VERSION 5.7 ;
  NOWIREEXTENSIONATPIN ON ;
  DIVIDERCHAR "/" ;
  BUSBITCHARS "[]" ;
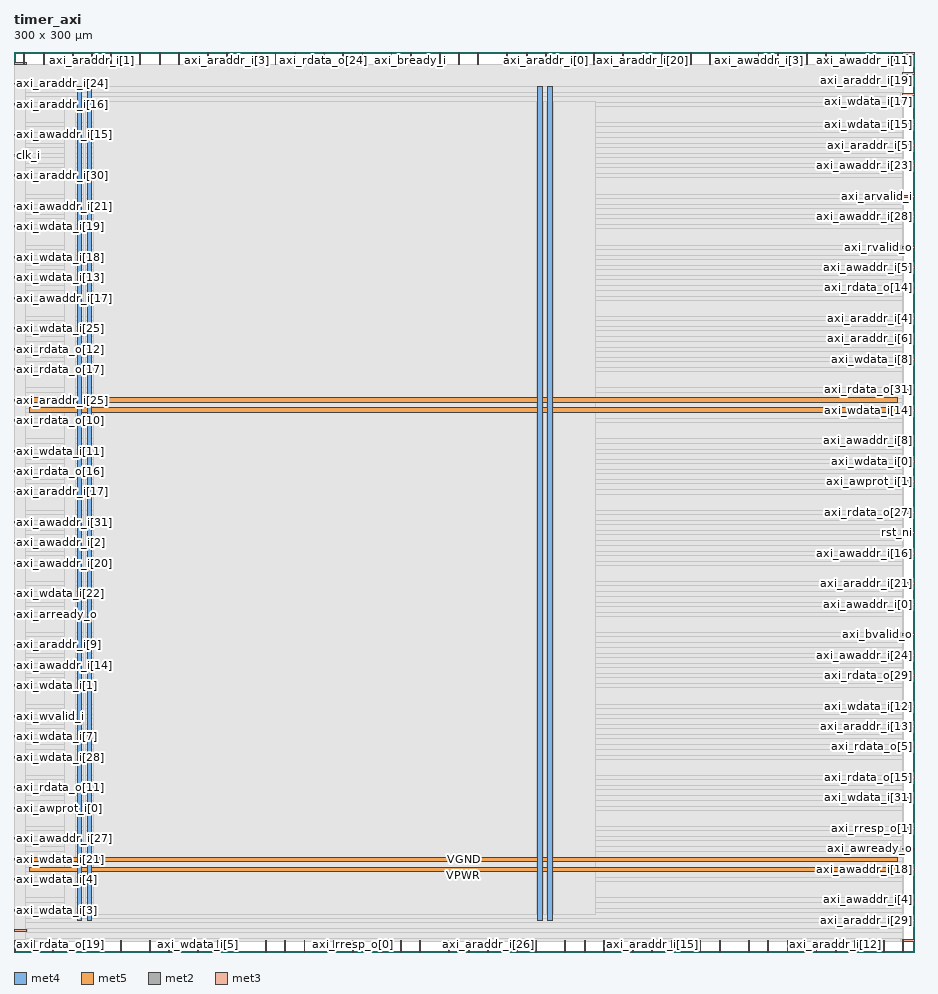
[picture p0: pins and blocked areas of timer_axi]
MACRO timer_axi
  CLASS BLOCK ;
  FOREIGN timer_axi ;
  ORIGIN 0.000 0.000 ;
  SIZE 300.000 BY 300.000 ;
  PIN VGND
    DIRECTION INOUT ;
    USE GROUND ;
    PORT
      LAYER met4 ;
        RECT 24.340 10.640 25.940 288.560 ;
    END
    PORT
      LAYER met4 ;
        RECT 177.940 10.640 179.540 288.560 ;
    END
    PORT
      LAYER met5 ;
        RECT 5.280 30.030 294.640 31.630 ;
    END
    PORT
      LAYER met5 ;
        RECT 5.280 183.210 294.640 184.810 ;
    END
  END VGND
  PIN VPWR
    DIRECTION INOUT ;
    USE POWER ;
    PORT
      LAYER met4 ;
        RECT 21.040 10.640 22.640 288.560 ;
    END
    PORT
      LAYER met4 ;
        RECT 174.640 10.640 176.240 288.560 ;
    END
    PORT
      LAYER met5 ;
        RECT 5.280 26.730 294.640 28.330 ;
    END
    PORT
      LAYER met5 ;
        RECT 5.280 179.910 294.640 181.510 ;
    END
  END VPWR
  PIN axi_araddr_i[0]
    DIRECTION INPUT ;
    USE SIGNAL ;
    PORT
      LAYER met2 ;
        RECT 177.190 296.000 177.470 300.000 ;
    END
  END axi_araddr_i[0]
  PIN axi_araddr_i[10]
    DIRECTION INPUT ;
    USE SIGNAL ;
    PORT
      LAYER met2 ;
        RECT 19.410 296.000 19.690 300.000 ;
    END
  END axi_araddr_i[10]
  PIN axi_araddr_i[11]
    DIRECTION INPUT ;
    USE SIGNAL ;
    PORT
      LAYER met2 ;
        RECT 141.770 296.000 142.050 300.000 ;
    END
  END axi_araddr_i[11]
  PIN axi_araddr_i[12]
    DIRECTION INPUT ;
    USE SIGNAL ;
    PORT
      LAYER met2 ;
        RECT 273.790 0.000 274.070 4.000 ;
    END
  END axi_araddr_i[12]
  PIN axi_araddr_i[13]
    DIRECTION INPUT ;
    USE SIGNAL ;
    PORT
      LAYER met3 ;
        RECT 296.000 74.840 300.000 75.440 ;
    END
  END axi_araddr_i[13]
  PIN axi_araddr_i[14]
    DIRECTION INPUT ;
    USE SIGNAL ;
    PORT
      LAYER met2 ;
        RECT 164.310 296.000 164.590 300.000 ;
    END
  END axi_araddr_i[14]
  PIN axi_araddr_i[15]
    DIRECTION INPUT ;
    USE SIGNAL ;
    PORT
      LAYER met2 ;
        RECT 212.610 0.000 212.890 4.000 ;
    END
  END axi_araddr_i[15]
  PIN axi_araddr_i[16]
    DIRECTION INPUT ;
    USE SIGNAL ;
    PORT
      LAYER met3 ;
        RECT 0.000 282.240 4.000 282.840 ;
    END
  END axi_araddr_i[16]
  PIN axi_araddr_i[17]
    DIRECTION INPUT ;
    USE SIGNAL ;
    PORT
      LAYER met3 ;
        RECT 0.000 153.040 4.000 153.640 ;
    END
  END axi_araddr_i[17]
  PIN axi_araddr_i[18]
    DIRECTION INPUT ;
    USE SIGNAL ;
    PORT
      LAYER met2 ;
        RECT 87.030 296.000 87.310 300.000 ;
    END
  END axi_araddr_i[18]
  PIN axi_araddr_i[19]
    DIRECTION INPUT ;
    USE SIGNAL ;
    PORT
      LAYER met3 ;
        RECT 296.000 292.440 300.000 293.040 ;
    END
  END axi_araddr_i[19]
  PIN axi_araddr_i[1]
    DIRECTION INPUT ;
    USE SIGNAL ;
    PORT
      LAYER met2 ;
        RECT 25.850 296.000 26.130 300.000 ;
    END
  END axi_araddr_i[1]
  PIN axi_araddr_i[20]
    DIRECTION INPUT ;
    USE SIGNAL ;
    PORT
      LAYER met2 ;
        RECT 209.390 296.000 209.670 300.000 ;
    END
  END axi_araddr_i[20]
  PIN axi_araddr_i[21]
    DIRECTION INPUT ;
    USE SIGNAL ;
    PORT
      LAYER met3 ;
        RECT 296.000 122.440 300.000 123.040 ;
    END
  END axi_araddr_i[21]
  PIN axi_araddr_i[22]
    DIRECTION INPUT ;
    USE SIGNAL ;
    PORT
      LAYER met2 ;
        RECT 125.670 296.000 125.950 300.000 ;
    END
  END axi_araddr_i[22]
  PIN axi_araddr_i[23]
    DIRECTION INPUT ;
    USE SIGNAL ;
    PORT
      LAYER met2 ;
        RECT 257.690 0.000 257.970 4.000 ;
    END
  END axi_araddr_i[23]
  PIN axi_araddr_i[24]
    DIRECTION INPUT ;
    USE SIGNAL ;
    PORT
      LAYER met3 ;
        RECT 0.000 289.040 4.000 289.640 ;
    END
  END axi_araddr_i[24]
  PIN axi_araddr_i[25]
    DIRECTION INPUT ;
    USE SIGNAL ;
    PORT
      LAYER met3 ;
        RECT 0.000 183.640 4.000 184.240 ;
    END
  END axi_araddr_i[25]
  PIN axi_araddr_i[26]
    DIRECTION INPUT ;
    USE SIGNAL ;
    PORT
      LAYER met2 ;
        RECT 157.870 0.000 158.150 4.000 ;
    END
  END axi_araddr_i[26]
  PIN axi_araddr_i[27]
    DIRECTION INPUT ;
    USE SIGNAL ;
    PORT
      LAYER met2 ;
        RECT 228.710 0.000 228.990 4.000 ;
    END
  END axi_araddr_i[27]
  PIN axi_araddr_i[28]
    DIRECTION INPUT ;
    USE SIGNAL ;
    PORT
      LAYER met3 ;
        RECT 0.000 295.840 4.000 296.440 ;
    END
  END axi_araddr_i[28]
  PIN axi_araddr_i[29]
    DIRECTION INPUT ;
    USE SIGNAL ;
    PORT
      LAYER met3 ;
        RECT 296.000 10.240 300.000 10.840 ;
    END
  END axi_araddr_i[29]
  PIN axi_araddr_i[2]
    DIRECTION INPUT ;
    USE SIGNAL ;
    ANTENNAGATEAREA 0.213000 ;
    PORT
      LAYER met2 ;
        RECT 45.170 0.000 45.450 4.000 ;
    END
  END axi_araddr_i[2]
  PIN axi_araddr_i[30]
    DIRECTION INPUT ;
    USE SIGNAL ;
    PORT
      LAYER met3 ;
        RECT 0.000 258.440 4.000 259.040 ;
    END
  END axi_araddr_i[30]
  PIN axi_araddr_i[31]
    DIRECTION INPUT ;
    USE SIGNAL ;
    PORT
      LAYER met2 ;
        RECT 193.290 296.000 193.570 300.000 ;
    END
  END axi_araddr_i[31]
  PIN axi_araddr_i[3]
    DIRECTION INPUT ;
    USE SIGNAL ;
    ANTENNAGATEAREA 0.159000 ;
    PORT
      LAYER met2 ;
        RECT 70.930 296.000 71.210 300.000 ;
    END
  END axi_araddr_i[3]
  PIN axi_araddr_i[4]
    DIRECTION INPUT ;
    USE SIGNAL ;
    ANTENNAGATEAREA 0.213000 ;
    PORT
      LAYER met3 ;
        RECT 296.000 210.840 300.000 211.440 ;
    END
  END axi_araddr_i[4]
  PIN axi_araddr_i[5]
    DIRECTION INPUT ;
    USE SIGNAL ;
    PORT
      LAYER met3 ;
        RECT 296.000 268.640 300.000 269.240 ;
    END
  END axi_araddr_i[5]
  PIN axi_araddr_i[6]
    DIRECTION INPUT ;
    USE SIGNAL ;
    PORT
      LAYER met3 ;
        RECT 296.000 204.040 300.000 204.640 ;
    END
  END axi_araddr_i[6]
  PIN axi_araddr_i[7]
    DIRECTION INPUT ;
    USE SIGNAL ;
    PORT
      LAYER met3 ;
        RECT 296.000 299.240 300.000 299.840 ;
    END
  END axi_araddr_i[7]
  PIN axi_araddr_i[8]
    DIRECTION INPUT ;
    USE SIGNAL ;
    PORT
      LAYER met2 ;
        RECT 122.450 0.000 122.730 4.000 ;
    END
  END axi_araddr_i[8]
  PIN axi_araddr_i[9]
    DIRECTION INPUT ;
    USE SIGNAL ;
    PORT
      LAYER met3 ;
        RECT 0.000 102.040 4.000 102.640 ;
    END
  END axi_araddr_i[9]
  PIN axi_arprot_i[0]
    DIRECTION INPUT ;
    USE SIGNAL ;
    PORT
      LAYER met2 ;
        RECT 231.930 296.000 232.210 300.000 ;
    END
  END axi_arprot_i[0]
  PIN axi_arprot_i[1]
    DIRECTION INPUT ;
    USE SIGNAL ;
    PORT
      LAYER met2 ;
        RECT 96.690 0.000 96.970 4.000 ;
    END
  END axi_arprot_i[1]
  PIN axi_arprot_i[2]
    DIRECTION INPUT ;
    USE SIGNAL ;
    PORT
      LAYER met2 ;
        RECT 219.050 0.000 219.330 4.000 ;
    END
  END axi_arprot_i[2]
  PIN axi_arready_o
    DIRECTION OUTPUT TRISTATE ;
    USE SIGNAL ;
    ANTENNADIFFAREA 0.795200 ;
    PORT
      LAYER met3 ;
        RECT 0.000 112.240 4.000 112.840 ;
    END
  END axi_arready_o
  PIN axi_arvalid_i
    DIRECTION INPUT ;
    USE SIGNAL ;
    ANTENNAGATEAREA 0.159000 ;
    PORT
      LAYER met3 ;
        RECT 296.000 251.640 300.000 252.240 ;
    END
  END axi_arvalid_i
  PIN axi_awaddr_i[0]
    DIRECTION INPUT ;
    USE SIGNAL ;
    PORT
      LAYER met3 ;
        RECT 296.000 115.640 300.000 116.240 ;
    END
  END axi_awaddr_i[0]
  PIN axi_awaddr_i[10]
    DIRECTION INPUT ;
    USE SIGNAL ;
    PORT
      LAYER met2 ;
        RECT 116.010 296.000 116.290 300.000 ;
    END
  END axi_awaddr_i[10]
  PIN axi_awaddr_i[11]
    DIRECTION INPUT ;
    USE SIGNAL ;
    PORT
      LAYER met2 ;
        RECT 286.670 296.000 286.950 300.000 ;
    END
  END axi_awaddr_i[11]
  PIN axi_awaddr_i[12]
    DIRECTION INPUT ;
    USE SIGNAL ;
    PORT
      LAYER met2 ;
        RECT 173.970 0.000 174.250 4.000 ;
    END
  END axi_awaddr_i[12]
  PIN axi_awaddr_i[13]
    DIRECTION INPUT ;
    USE SIGNAL ;
    PORT
      LAYER met2 ;
        RECT 22.630 0.000 22.910 4.000 ;
    END
  END axi_awaddr_i[13]
  PIN axi_awaddr_i[14]
    DIRECTION INPUT ;
    USE SIGNAL ;
    PORT
      LAYER met3 ;
        RECT 0.000 95.240 4.000 95.840 ;
    END
  END axi_awaddr_i[14]
  PIN axi_awaddr_i[15]
    DIRECTION INPUT ;
    USE SIGNAL ;
    PORT
      LAYER met3 ;
        RECT 0.000 272.040 4.000 272.640 ;
    END
  END axi_awaddr_i[15]
  PIN axi_awaddr_i[16]
    DIRECTION INPUT ;
    USE SIGNAL ;
    PORT
      LAYER met3 ;
        RECT 296.000 132.640 300.000 133.240 ;
    END
  END axi_awaddr_i[16]
  PIN axi_awaddr_i[17]
    DIRECTION INPUT ;
    USE SIGNAL ;
    PORT
      LAYER met3 ;
        RECT 0.000 217.640 4.000 218.240 ;
    END
  END axi_awaddr_i[17]
  PIN axi_awaddr_i[18]
    DIRECTION INPUT ;
    USE SIGNAL ;
    PORT
      LAYER met3 ;
        RECT 296.000 27.240 300.000 27.840 ;
    END
  END axi_awaddr_i[18]
  PIN axi_awaddr_i[19]
    DIRECTION INPUT ;
    USE SIGNAL ;
    PORT
      LAYER met2 ;
        RECT 186.850 296.000 187.130 300.000 ;
    END
  END axi_awaddr_i[19]
  PIN axi_awaddr_i[1]
    DIRECTION INPUT ;
    USE SIGNAL ;
    PORT
      LAYER met2 ;
        RECT 238.370 296.000 238.650 300.000 ;
    END
  END axi_awaddr_i[1]
  PIN axi_awaddr_i[20]
    DIRECTION INPUT ;
    USE SIGNAL ;
    PORT
      LAYER met3 ;
        RECT 0.000 129.240 4.000 129.840 ;
    END
  END axi_awaddr_i[20]
  PIN axi_awaddr_i[21]
    DIRECTION INPUT ;
    USE SIGNAL ;
    PORT
      LAYER met3 ;
        RECT 0.000 248.240 4.000 248.840 ;
    END
  END axi_awaddr_i[21]
  PIN axi_awaddr_i[22]
    DIRECTION INPUT ;
    USE SIGNAL ;
    PORT
      LAYER met2 ;
        RECT 202.950 296.000 203.230 300.000 ;
    END
  END axi_awaddr_i[22]
  PIN axi_awaddr_i[23]
    DIRECTION INPUT ;
    USE SIGNAL ;
    PORT
      LAYER met3 ;
        RECT 296.000 261.840 300.000 262.440 ;
    END
  END axi_awaddr_i[23]
  PIN axi_awaddr_i[24]
    DIRECTION INPUT ;
    USE SIGNAL ;
    PORT
      LAYER met3 ;
        RECT 296.000 98.640 300.000 99.240 ;
    END
  END axi_awaddr_i[24]
  PIN axi_awaddr_i[25]
    DIRECTION INPUT ;
    USE SIGNAL ;
    PORT
      LAYER met2 ;
        RECT 277.010 296.000 277.290 300.000 ;
    END
  END axi_awaddr_i[25]
  PIN axi_awaddr_i[26]
    DIRECTION INPUT ;
    USE SIGNAL ;
    PORT
      LAYER met2 ;
        RECT 74.150 0.000 74.430 4.000 ;
    END
  END axi_awaddr_i[26]
  PIN axi_awaddr_i[27]
    DIRECTION INPUT ;
    USE SIGNAL ;
    PORT
      LAYER met3 ;
        RECT 0.000 37.440 4.000 38.040 ;
    END
  END axi_awaddr_i[27]
  PIN axi_awaddr_i[28]
    DIRECTION INPUT ;
    USE SIGNAL ;
    PORT
      LAYER met3 ;
        RECT 296.000 244.840 300.000 245.440 ;
    END
  END axi_awaddr_i[28]
  PIN axi_awaddr_i[29]
    DIRECTION INPUT ;
    USE SIGNAL ;
    PORT
      LAYER met2 ;
        RECT 90.250 0.000 90.530 4.000 ;
    END
  END axi_awaddr_i[29]
  PIN axi_awaddr_i[2]
    DIRECTION INPUT ;
    USE SIGNAL ;
    ANTENNAGATEAREA 0.213000 ;
    PORT
      LAYER met3 ;
        RECT 0.000 136.040 4.000 136.640 ;
    END
  END axi_awaddr_i[2]
  PIN axi_awaddr_i[30]
    DIRECTION INPUT ;
    USE SIGNAL ;
    PORT
      LAYER met2 ;
        RECT 190.070 0.000 190.350 4.000 ;
    END
  END axi_awaddr_i[30]
  PIN axi_awaddr_i[31]
    DIRECTION INPUT ;
    USE SIGNAL ;
    PORT
      LAYER met3 ;
        RECT 0.000 142.840 4.000 143.440 ;
    END
  END axi_awaddr_i[31]
  PIN axi_awaddr_i[3]
    DIRECTION INPUT ;
    USE SIGNAL ;
    ANTENNAGATEAREA 0.247500 ;
    PORT
      LAYER met2 ;
        RECT 248.030 296.000 248.310 300.000 ;
    END
  END axi_awaddr_i[3]
  PIN axi_awaddr_i[4]
    DIRECTION INPUT ;
    USE SIGNAL ;
    ANTENNAGATEAREA 0.213000 ;
    PORT
      LAYER met3 ;
        RECT 296.000 17.040 300.000 17.640 ;
    END
  END axi_awaddr_i[4]
  PIN axi_awaddr_i[5]
    DIRECTION INPUT ;
    USE SIGNAL ;
    PORT
      LAYER met3 ;
        RECT 296.000 227.840 300.000 228.440 ;
    END
  END axi_awaddr_i[5]
  PIN axi_awaddr_i[6]
    DIRECTION INPUT ;
    USE SIGNAL ;
    PORT
      LAYER met2 ;
        RECT 128.890 0.000 129.170 4.000 ;
    END
  END axi_awaddr_i[6]
  PIN axi_awaddr_i[7]
    DIRECTION INPUT ;
    USE SIGNAL ;
    PORT
      LAYER met2 ;
        RECT 196.510 0.000 196.790 4.000 ;
    END
  END axi_awaddr_i[7]
  PIN axi_awaddr_i[8]
    DIRECTION INPUT ;
    USE SIGNAL ;
    PORT
      LAYER met3 ;
        RECT 296.000 170.040 300.000 170.640 ;
    END
  END axi_awaddr_i[8]
  PIN axi_awaddr_i[9]
    DIRECTION INPUT ;
    USE SIGNAL ;
    PORT
      LAYER met2 ;
        RECT 83.810 0.000 84.090 4.000 ;
    END
  END axi_awaddr_i[9]
  PIN axi_awprot_i[0]
    DIRECTION INPUT ;
    USE SIGNAL ;
    PORT
      LAYER met3 ;
        RECT 0.000 47.640 4.000 48.240 ;
    END
  END axi_awprot_i[0]
  PIN axi_awprot_i[1]
    DIRECTION INPUT ;
    USE SIGNAL ;
    PORT
      LAYER met3 ;
        RECT 296.000 156.440 300.000 157.040 ;
    END
  END axi_awprot_i[1]
  PIN axi_awprot_i[2]
    DIRECTION INPUT ;
    USE SIGNAL ;
    PORT
      LAYER met2 ;
        RECT 267.350 0.000 267.630 4.000 ;
    END
  END axi_awprot_i[2]
  PIN axi_awready_o
    DIRECTION OUTPUT TRISTATE ;
    USE SIGNAL ;
    ANTENNADIFFAREA 0.795200 ;
    PORT
      LAYER met3 ;
        RECT 296.000 34.040 300.000 34.640 ;
    END
  END axi_awready_o
  PIN axi_awvalid_i
    DIRECTION INPUT ;
    USE SIGNAL ;
    ANTENNAGATEAREA 0.213000 ;
    PORT
      LAYER met2 ;
        RECT 93.470 296.000 93.750 300.000 ;
    END
  END axi_awvalid_i
  PIN axi_bready_i
    DIRECTION INPUT ;
    USE SIGNAL ;
    ANTENNAGATEAREA 0.196500 ;
    PORT
      LAYER met2 ;
        RECT 132.110 296.000 132.390 300.000 ;
    END
  END axi_bready_i
  PIN axi_bresp_o[0]
    DIRECTION OUTPUT TRISTATE ;
    USE SIGNAL ;
    PORT
      LAYER met2 ;
        RECT 9.750 296.000 10.030 300.000 ;
    END
  END axi_bresp_o[0]
  PIN axi_bresp_o[1]
    DIRECTION OUTPUT TRISTATE ;
    USE SIGNAL ;
    PORT
      LAYER met2 ;
        RECT 293.110 296.000 293.390 300.000 ;
    END
  END axi_bresp_o[1]
  PIN axi_bvalid_o
    DIRECTION OUTPUT TRISTATE ;
    USE SIGNAL ;
    ANTENNADIFFAREA 0.445500 ;
    PORT
      LAYER met3 ;
        RECT 296.000 105.440 300.000 106.040 ;
    END
  END axi_bvalid_o
  PIN axi_rdata_o[0]
    DIRECTION OUTPUT TRISTATE ;
    USE SIGNAL ;
    ANTENNADIFFAREA 0.795200 ;
    PORT
      LAYER met2 ;
        RECT 135.330 0.000 135.610 4.000 ;
    END
  END axi_rdata_o[0]
  PIN axi_rdata_o[10]
    DIRECTION OUTPUT TRISTATE ;
    USE SIGNAL ;
    ANTENNADIFFAREA 0.795200 ;
    PORT
      LAYER met3 ;
        RECT 0.000 176.840 4.000 177.440 ;
    END
  END axi_rdata_o[10]
  PIN axi_rdata_o[11]
    DIRECTION OUTPUT TRISTATE ;
    USE SIGNAL ;
    ANTENNADIFFAREA 0.795200 ;
    PORT
      LAYER met3 ;
        RECT 0.000 54.440 4.000 55.040 ;
    END
  END axi_rdata_o[11]
  PIN axi_rdata_o[12]
    DIRECTION OUTPUT TRISTATE ;
    USE SIGNAL ;
    ANTENNADIFFAREA 0.795200 ;
    PORT
      LAYER met3 ;
        RECT 0.000 200.640 4.000 201.240 ;
    END
  END axi_rdata_o[12]
  PIN axi_rdata_o[13]
    DIRECTION OUTPUT TRISTATE ;
    USE SIGNAL ;
    ANTENNADIFFAREA 0.795200 ;
    PORT
      LAYER met2 ;
        RECT 235.150 0.000 235.430 4.000 ;
    END
  END axi_rdata_o[13]
  PIN axi_rdata_o[14]
    DIRECTION OUTPUT TRISTATE ;
    USE SIGNAL ;
    ANTENNADIFFAREA 0.445500 ;
    PORT
      LAYER met3 ;
        RECT 296.000 221.040 300.000 221.640 ;
    END
  END axi_rdata_o[14]
  PIN axi_rdata_o[15]
    DIRECTION OUTPUT TRISTATE ;
    USE SIGNAL ;
    ANTENNADIFFAREA 0.445500 ;
    PORT
      LAYER met3 ;
        RECT 296.000 57.840 300.000 58.440 ;
    END
  END axi_rdata_o[15]
  PIN axi_rdata_o[16]
    DIRECTION OUTPUT TRISTATE ;
    USE SIGNAL ;
    ANTENNADIFFAREA 0.795200 ;
    PORT
      LAYER met3 ;
        RECT 0.000 159.840 4.000 160.440 ;
    END
  END axi_rdata_o[16]
  PIN axi_rdata_o[17]
    DIRECTION OUTPUT TRISTATE ;
    USE SIGNAL ;
    ANTENNADIFFAREA 0.795200 ;
    PORT
      LAYER met3 ;
        RECT 0.000 193.840 4.000 194.440 ;
    END
  END axi_rdata_o[17]
  PIN axi_rdata_o[18]
    DIRECTION OUTPUT TRISTATE ;
    USE SIGNAL ;
    ANTENNADIFFAREA 0.795200 ;
    PORT
      LAYER met2 ;
        RECT 254.470 296.000 254.750 300.000 ;
    END
  END axi_rdata_o[18]
  PIN axi_rdata_o[19]
    DIRECTION OUTPUT TRISTATE ;
    USE SIGNAL ;
    ANTENNADIFFAREA 0.795200 ;
    PORT
      LAYER met2 ;
        RECT 6.530 0.000 6.810 4.000 ;
    END
  END axi_rdata_o[19]
  PIN axi_rdata_o[1]
    DIRECTION OUTPUT TRISTATE ;
    USE SIGNAL ;
    ANTENNADIFFAREA 0.795200 ;
    PORT
      LAYER met2 ;
        RECT 48.390 296.000 48.670 300.000 ;
    END
  END axi_rdata_o[1]
  PIN axi_rdata_o[20]
    DIRECTION OUTPUT TRISTATE ;
    USE SIGNAL ;
    ANTENNADIFFAREA 0.795200 ;
    PORT
      LAYER met3 ;
        RECT 296.000 3.440 300.000 4.040 ;
    END
  END axi_rdata_o[20]
  PIN axi_rdata_o[21]
    DIRECTION OUTPUT TRISTATE ;
    USE SIGNAL ;
    ANTENNADIFFAREA 0.795200 ;
    PORT
      LAYER met2 ;
        RECT 41.950 296.000 42.230 300.000 ;
    END
  END axi_rdata_o[21]
  PIN axi_rdata_o[22]
    DIRECTION OUTPUT TRISTATE ;
    USE SIGNAL ;
    ANTENNADIFFAREA 0.795200 ;
    PORT
      LAYER met2 ;
        RECT 109.570 296.000 109.850 300.000 ;
    END
  END axi_rdata_o[22]
  PIN axi_rdata_o[23]
    DIRECTION OUTPUT TRISTATE ;
    USE SIGNAL ;
    ANTENNADIFFAREA 0.795200 ;
    PORT
      LAYER met3 ;
        RECT 0.000 6.840 4.000 7.440 ;
    END
  END axi_rdata_o[23]
  PIN axi_rdata_o[24]
    DIRECTION OUTPUT TRISTATE ;
    USE SIGNAL ;
    ANTENNADIFFAREA 0.795200 ;
    PORT
      LAYER met2 ;
        RECT 103.130 296.000 103.410 300.000 ;
    END
  END axi_rdata_o[24]
  PIN axi_rdata_o[25]
    DIRECTION OUTPUT TRISTATE ;
    USE SIGNAL ;
    ANTENNADIFFAREA 0.795200 ;
    PORT
      LAYER met2 ;
        RECT 29.070 0.000 29.350 4.000 ;
    END
  END axi_rdata_o[25]
  PIN axi_rdata_o[26]
    DIRECTION OUTPUT TRISTATE ;
    USE SIGNAL ;
    ANTENNADIFFAREA 0.795200 ;
    PORT
      LAYER met2 ;
        RECT 32.290 296.000 32.570 300.000 ;
    END
  END axi_rdata_o[26]
  PIN axi_rdata_o[27]
    DIRECTION OUTPUT TRISTATE ;
    USE SIGNAL ;
    ANTENNADIFFAREA 0.445500 ;
    PORT
      LAYER met3 ;
        RECT 296.000 146.240 300.000 146.840 ;
    END
  END axi_rdata_o[27]
  PIN axi_rdata_o[28]
    DIRECTION OUTPUT TRISTATE ;
    USE SIGNAL ;
    ANTENNADIFFAREA 0.795200 ;
    PORT
      LAYER met2 ;
        RECT 148.210 296.000 148.490 300.000 ;
    END
  END axi_rdata_o[28]
  PIN axi_rdata_o[29]
    DIRECTION OUTPUT TRISTATE ;
    USE SIGNAL ;
    ANTENNADIFFAREA 0.445500 ;
    PORT
      LAYER met3 ;
        RECT 296.000 91.840 300.000 92.440 ;
    END
  END axi_rdata_o[29]
  PIN axi_rdata_o[2]
    DIRECTION OUTPUT TRISTATE ;
    USE SIGNAL ;
    ANTENNADIFFAREA 0.795200 ;
    PORT
      LAYER met2 ;
        RECT 289.890 0.000 290.170 4.000 ;
    END
  END axi_rdata_o[2]
  PIN axi_rdata_o[30]
    DIRECTION OUTPUT TRISTATE ;
    USE SIGNAL ;
    ANTENNADIFFAREA 0.795200 ;
    PORT
      LAYER met2 ;
        RECT 151.430 0.000 151.710 4.000 ;
    END
  END axi_rdata_o[30]
  PIN axi_rdata_o[31]
    DIRECTION OUTPUT TRISTATE ;
    USE SIGNAL ;
    ANTENNADIFFAREA 0.445500 ;
    PORT
      LAYER met3 ;
        RECT 296.000 187.040 300.000 187.640 ;
    END
  END axi_rdata_o[31]
  PIN axi_rdata_o[3]
    DIRECTION OUTPUT TRISTATE ;
    USE SIGNAL ;
    ANTENNADIFFAREA 0.795200 ;
    PORT
      LAYER met2 ;
        RECT 270.570 296.000 270.850 300.000 ;
    END
  END axi_rdata_o[3]
  PIN axi_rdata_o[4]
    DIRECTION OUTPUT TRISTATE ;
    USE SIGNAL ;
    ANTENNADIFFAREA 0.795200 ;
    PORT
      LAYER met2 ;
        RECT 67.710 0.000 67.990 4.000 ;
    END
  END axi_rdata_o[4]
  PIN axi_rdata_o[5]
    DIRECTION OUTPUT TRISTATE ;
    USE SIGNAL ;
    ANTENNADIFFAREA 0.795200 ;
    PORT
      LAYER met3 ;
        RECT 296.000 68.040 300.000 68.640 ;
    END
  END axi_rdata_o[5]
  PIN axi_rdata_o[6]
    DIRECTION OUTPUT TRISTATE ;
    USE SIGNAL ;
    ANTENNADIFFAREA 0.795200 ;
    PORT
      LAYER met2 ;
        RECT 183.630 0.000 183.910 4.000 ;
    END
  END axi_rdata_o[6]
  PIN axi_rdata_o[7]
    DIRECTION OUTPUT TRISTATE ;
    USE SIGNAL ;
    ANTENNADIFFAREA 0.795200 ;
    PORT
      LAYER met2 ;
        RECT 296.330 0.000 296.610 4.000 ;
    END
  END axi_rdata_o[7]
  PIN axi_rdata_o[8]
    DIRECTION OUTPUT TRISTATE ;
    USE SIGNAL ;
    ANTENNADIFFAREA 0.795200 ;
    PORT
      LAYER met2 ;
        RECT 80.590 296.000 80.870 300.000 ;
    END
  END axi_rdata_o[8]
  PIN axi_rdata_o[9]
    DIRECTION OUTPUT TRISTATE ;
    USE SIGNAL ;
    ANTENNADIFFAREA 0.795200 ;
    PORT
      LAYER met2 ;
        RECT 244.810 0.000 245.090 4.000 ;
    END
  END axi_rdata_o[9]
  PIN axi_rready_i
    DIRECTION INPUT ;
    USE SIGNAL ;
    ANTENNAGATEAREA 0.196500 ;
    PORT
      LAYER met2 ;
        RECT 35.510 0.000 35.790 4.000 ;
    END
  END axi_rready_i
  PIN axi_rresp_o[0]
    DIRECTION OUTPUT TRISTATE ;
    USE SIGNAL ;
    PORT
      LAYER met2 ;
        RECT 112.790 0.000 113.070 4.000 ;
    END
  END axi_rresp_o[0]
  PIN axi_rresp_o[1]
    DIRECTION OUTPUT TRISTATE ;
    USE SIGNAL ;
    PORT
      LAYER met3 ;
        RECT 296.000 40.840 300.000 41.440 ;
    END
  END axi_rresp_o[1]
  PIN axi_rvalid_o
    DIRECTION OUTPUT TRISTATE ;
    USE SIGNAL ;
    ANTENNADIFFAREA 0.445500 ;
    PORT
      LAYER met3 ;
        RECT 296.000 234.640 300.000 235.240 ;
    END
  END axi_rvalid_o
  PIN axi_wdata_i[0]
    DIRECTION INPUT ;
    USE SIGNAL ;
    ANTENNAGATEAREA 0.213000 ;
    PORT
      LAYER met3 ;
        RECT 296.000 163.240 300.000 163.840 ;
    END
  END axi_wdata_i[0]
  PIN axi_wdata_i[10]
    DIRECTION INPUT ;
    USE SIGNAL ;
    ANTENNAGATEAREA 0.213000 ;
    PORT
      LAYER met2 ;
        RECT 251.250 0.000 251.530 4.000 ;
    END
  END axi_wdata_i[10]
  PIN axi_wdata_i[11]
    DIRECTION INPUT ;
    USE SIGNAL ;
    ANTENNAGATEAREA 0.196500 ;
    PORT
      LAYER met3 ;
        RECT 0.000 166.640 4.000 167.240 ;
    END
  END axi_wdata_i[11]
  PIN axi_wdata_i[12]
    DIRECTION INPUT ;
    USE SIGNAL ;
    ANTENNAGATEAREA 0.213000 ;
    PORT
      LAYER met3 ;
        RECT 296.000 81.640 300.000 82.240 ;
    END
  END axi_wdata_i[12]
  PIN axi_wdata_i[13]
    DIRECTION INPUT ;
    USE SIGNAL ;
    ANTENNAGATEAREA 0.126000 ;
    PORT
      LAYER met3 ;
        RECT 0.000 224.440 4.000 225.040 ;
    END
  END axi_wdata_i[13]
  PIN axi_wdata_i[14]
    DIRECTION INPUT ;
    USE SIGNAL ;
    ANTENNAGATEAREA 0.213000 ;
    PORT
      LAYER met3 ;
        RECT 296.000 180.240 300.000 180.840 ;
    END
  END axi_wdata_i[14]
  PIN axi_wdata_i[15]
    DIRECTION INPUT ;
    USE SIGNAL ;
    ANTENNAGATEAREA 0.159000 ;
    PORT
      LAYER met3 ;
        RECT 296.000 275.440 300.000 276.040 ;
    END
  END axi_wdata_i[15]
  PIN axi_wdata_i[16]
    DIRECTION INPUT ;
    USE SIGNAL ;
    ANTENNAGATEAREA 0.159000 ;
    PORT
      LAYER met2 ;
        RECT 280.230 0.000 280.510 4.000 ;
    END
  END axi_wdata_i[16]
  PIN axi_wdata_i[17]
    DIRECTION INPUT ;
    USE SIGNAL ;
    ANTENNAGATEAREA 0.159000 ;
    PORT
      LAYER met3 ;
        RECT 296.000 285.640 300.000 286.240 ;
    END
  END axi_wdata_i[17]
  PIN axi_wdata_i[18]
    DIRECTION INPUT ;
    USE SIGNAL ;
    ANTENNAGATEAREA 0.196500 ;
    PORT
      LAYER met3 ;
        RECT 0.000 231.240 4.000 231.840 ;
    END
  END axi_wdata_i[18]
  PIN axi_wdata_i[19]
    DIRECTION INPUT ;
    USE SIGNAL ;
    ANTENNAGATEAREA 0.196500 ;
    PORT
      LAYER met3 ;
        RECT 0.000 241.440 4.000 242.040 ;
    END
  END axi_wdata_i[19]
  PIN axi_wdata_i[1]
    DIRECTION INPUT ;
    USE SIGNAL ;
    ANTENNAGATEAREA 0.196500 ;
    PORT
      LAYER met3 ;
        RECT 0.000 88.440 4.000 89.040 ;
    END
  END axi_wdata_i[1]
  PIN axi_wdata_i[20]
    DIRECTION INPUT ;
    USE SIGNAL ;
    ANTENNAGATEAREA 0.126000 ;
    PORT
      LAYER met2 ;
        RECT 0.090 0.000 0.370 4.000 ;
    END
  END axi_wdata_i[20]
  PIN axi_wdata_i[21]
    DIRECTION INPUT ;
    USE SIGNAL ;
    ANTENNAGATEAREA 0.126000 ;
    PORT
      LAYER met3 ;
        RECT 0.000 30.640 4.000 31.240 ;
    END
  END axi_wdata_i[21]
  PIN axi_wdata_i[22]
    DIRECTION INPUT ;
    USE SIGNAL ;
    ANTENNAGATEAREA 0.196500 ;
    PORT
      LAYER met3 ;
        RECT 0.000 119.040 4.000 119.640 ;
    END
  END axi_wdata_i[22]
  PIN axi_wdata_i[23]
    DIRECTION INPUT ;
    USE SIGNAL ;
    ANTENNAGATEAREA 0.196500 ;
    PORT
      LAYER met2 ;
        RECT 64.490 296.000 64.770 300.000 ;
    END
  END axi_wdata_i[23]
  PIN axi_wdata_i[24]
    DIRECTION INPUT ;
    USE SIGNAL ;
    ANTENNAGATEAREA 0.213000 ;
    PORT
      LAYER met2 ;
        RECT 170.750 296.000 171.030 300.000 ;
    END
  END axi_wdata_i[24]
  PIN axi_wdata_i[25]
    DIRECTION INPUT ;
    USE SIGNAL ;
    ANTENNAGATEAREA 0.196500 ;
    PORT
      LAYER met3 ;
        RECT 0.000 207.440 4.000 208.040 ;
    END
  END axi_wdata_i[25]
  PIN axi_wdata_i[26]
    DIRECTION INPUT ;
    USE SIGNAL ;
    ANTENNAGATEAREA 0.126000 ;
    PORT
      LAYER met2 ;
        RECT 51.610 0.000 51.890 4.000 ;
    END
  END axi_wdata_i[26]
  PIN axi_wdata_i[27]
    DIRECTION INPUT ;
    USE SIGNAL ;
    ANTENNAGATEAREA 0.126000 ;
    PORT
      LAYER met2 ;
        RECT 12.970 0.000 13.250 4.000 ;
    END
  END axi_wdata_i[27]
  PIN axi_wdata_i[28]
    DIRECTION INPUT ;
    USE SIGNAL ;
    ANTENNAGATEAREA 0.196500 ;
    PORT
      LAYER met3 ;
        RECT 0.000 64.640 4.000 65.240 ;
    END
  END axi_wdata_i[28]
  PIN axi_wdata_i[29]
    DIRECTION INPUT ;
    USE SIGNAL ;
    ANTENNAGATEAREA 0.213000 ;
    PORT
      LAYER met2 ;
        RECT 154.650 296.000 154.930 300.000 ;
    END
  END axi_wdata_i[29]
  PIN axi_wdata_i[2]
    DIRECTION INPUT ;
    USE SIGNAL ;
    ANTENNAGATEAREA 0.196500 ;
    PORT
      LAYER met2 ;
        RECT 144.990 0.000 145.270 4.000 ;
    END
  END axi_wdata_i[2]
  PIN axi_wdata_i[30]
    DIRECTION INPUT ;
    USE SIGNAL ;
    ANTENNAGATEAREA 0.159000 ;
    PORT
      LAYER met2 ;
        RECT 264.130 296.000 264.410 300.000 ;
    END
  END axi_wdata_i[30]
  PIN axi_wdata_i[31]
    DIRECTION INPUT ;
    USE SIGNAL ;
    ANTENNAGATEAREA 0.213000 ;
    PORT
      LAYER met3 ;
        RECT 296.000 51.040 300.000 51.640 ;
    END
  END axi_wdata_i[31]
  PIN axi_wdata_i[3]
    DIRECTION INPUT ;
    USE SIGNAL ;
    ANTENNAGATEAREA 0.213000 ;
    PORT
      LAYER met3 ;
        RECT 0.000 13.640 4.000 14.240 ;
    END
  END axi_wdata_i[3]
  PIN axi_wdata_i[4]
    DIRECTION INPUT ;
    USE SIGNAL ;
    ANTENNAGATEAREA 0.196500 ;
    PORT
      LAYER met3 ;
        RECT 0.000 23.840 4.000 24.440 ;
    END
  END axi_wdata_i[4]
  PIN axi_wdata_i[5]
    DIRECTION INPUT ;
    USE SIGNAL ;
    ANTENNAGATEAREA 0.196500 ;
    PORT
      LAYER met2 ;
        RECT 61.270 0.000 61.550 4.000 ;
    END
  END axi_wdata_i[5]
  PIN axi_wdata_i[6]
    DIRECTION INPUT ;
    USE SIGNAL ;
    ANTENNAGATEAREA 0.196500 ;
    PORT
      LAYER met2 ;
        RECT 106.350 0.000 106.630 4.000 ;
    END
  END axi_wdata_i[6]
  PIN axi_wdata_i[7]
    DIRECTION INPUT ;
    USE SIGNAL ;
    ANTENNAGATEAREA 0.196500 ;
    PORT
      LAYER met3 ;
        RECT 0.000 71.440 4.000 72.040 ;
    END
  END axi_wdata_i[7]
  PIN axi_wdata_i[8]
    DIRECTION INPUT ;
    USE SIGNAL ;
    ANTENNAGATEAREA 0.159000 ;
    PORT
      LAYER met3 ;
        RECT 296.000 197.240 300.000 197.840 ;
    END
  END axi_wdata_i[8]
  PIN axi_wdata_i[9]
    DIRECTION INPUT ;
    USE SIGNAL ;
    ANTENNAGATEAREA 0.196500 ;
    PORT
      LAYER met2 ;
        RECT 167.530 0.000 167.810 4.000 ;
    END
  END axi_wdata_i[9]
  PIN axi_wready_o
    DIRECTION OUTPUT TRISTATE ;
    USE SIGNAL ;
    ANTENNADIFFAREA 0.795200 ;
    PORT
      LAYER met2 ;
        RECT 225.490 296.000 225.770 300.000 ;
    END
  END axi_wready_o
  PIN axi_wstrb_i[0]
    DIRECTION INPUT ;
    USE SIGNAL ;
    PORT
      LAYER met2 ;
        RECT 215.830 296.000 216.110 300.000 ;
    END
  END axi_wstrb_i[0]
  PIN axi_wstrb_i[1]
    DIRECTION INPUT ;
    USE SIGNAL ;
    PORT
      LAYER met2 ;
        RECT 3.310 296.000 3.590 300.000 ;
    END
  END axi_wstrb_i[1]
  PIN axi_wstrb_i[2]
    DIRECTION INPUT ;
    USE SIGNAL ;
    PORT
      LAYER met2 ;
        RECT 54.830 296.000 55.110 300.000 ;
    END
  END axi_wstrb_i[2]
  PIN axi_wstrb_i[3]
    DIRECTION INPUT ;
    USE SIGNAL ;
    PORT
      LAYER met2 ;
        RECT 206.170 0.000 206.450 4.000 ;
    END
  END axi_wstrb_i[3]
  PIN axi_wvalid_i
    DIRECTION INPUT ;
    USE SIGNAL ;
    ANTENNAGATEAREA 0.196500 ;
    PORT
      LAYER met3 ;
        RECT 0.000 78.240 4.000 78.840 ;
    END
  END axi_wvalid_i
  PIN clk_i
    DIRECTION INPUT ;
    USE SIGNAL ;
    ANTENNAGATEAREA 0.852000 ;
    PORT
      LAYER met3 ;
        RECT 0.000 265.240 4.000 265.840 ;
    END
  END clk_i
  PIN rst_ni
    DIRECTION INPUT ;
    USE SIGNAL ;
    ANTENNAGATEAREA 0.196500 ;
    PORT
      LAYER met3 ;
        RECT 296.000 139.440 300.000 140.040 ;
    END
  END rst_ni
  OBS
      LAYER li1 ;
        RECT 5.520 10.795 294.400 288.405 ;
      LAYER met1 ;
        RECT 0.070 9.900 296.630 288.560 ;
      LAYER met2 ;
        RECT 0.100 295.720 3.030 296.000 ;
        RECT 3.870 295.720 9.470 296.000 ;
        RECT 10.310 295.720 19.130 296.000 ;
        RECT 19.970 295.720 25.570 296.000 ;
        RECT 26.410 295.720 32.010 296.000 ;
        RECT 32.850 295.720 41.670 296.000 ;
        RECT 42.510 295.720 48.110 296.000 ;
        RECT 48.950 295.720 54.550 296.000 ;
        RECT 55.390 295.720 64.210 296.000 ;
        RECT 65.050 295.720 70.650 296.000 ;
        RECT 71.490 295.720 80.310 296.000 ;
        RECT 81.150 295.720 86.750 296.000 ;
        RECT 87.590 295.720 93.190 296.000 ;
        RECT 94.030 295.720 102.850 296.000 ;
        RECT 103.690 295.720 109.290 296.000 ;
        RECT 110.130 295.720 115.730 296.000 ;
        RECT 116.570 295.720 125.390 296.000 ;
        RECT 126.230 295.720 131.830 296.000 ;
        RECT 132.670 295.720 141.490 296.000 ;
        RECT 142.330 295.720 147.930 296.000 ;
        RECT 148.770 295.720 154.370 296.000 ;
        RECT 155.210 295.720 164.030 296.000 ;
        RECT 164.870 295.720 170.470 296.000 ;
        RECT 171.310 295.720 176.910 296.000 ;
        RECT 177.750 295.720 186.570 296.000 ;
        RECT 187.410 295.720 193.010 296.000 ;
        RECT 193.850 295.720 202.670 296.000 ;
        RECT 203.510 295.720 209.110 296.000 ;
        RECT 209.950 295.720 215.550 296.000 ;
        RECT 216.390 295.720 225.210 296.000 ;
        RECT 226.050 295.720 231.650 296.000 ;
        RECT 232.490 295.720 238.090 296.000 ;
        RECT 238.930 295.720 247.750 296.000 ;
        RECT 248.590 295.720 254.190 296.000 ;
        RECT 255.030 295.720 263.850 296.000 ;
        RECT 264.690 295.720 270.290 296.000 ;
        RECT 271.130 295.720 276.730 296.000 ;
        RECT 277.570 295.720 286.390 296.000 ;
        RECT 287.230 295.720 292.830 296.000 ;
        RECT 293.670 295.720 296.600 296.000 ;
        RECT 0.100 4.280 296.600 295.720 ;
        RECT 0.650 3.555 6.250 4.280 ;
        RECT 7.090 3.555 12.690 4.280 ;
        RECT 13.530 3.555 22.350 4.280 ;
        RECT 23.190 3.555 28.790 4.280 ;
        RECT 29.630 3.555 35.230 4.280 ;
        RECT 36.070 3.555 44.890 4.280 ;
        RECT 45.730 3.555 51.330 4.280 ;
        RECT 52.170 3.555 60.990 4.280 ;
        RECT 61.830 3.555 67.430 4.280 ;
        RECT 68.270 3.555 73.870 4.280 ;
        RECT 74.710 3.555 83.530 4.280 ;
        RECT 84.370 3.555 89.970 4.280 ;
        RECT 90.810 3.555 96.410 4.280 ;
        RECT 97.250 3.555 106.070 4.280 ;
        RECT 106.910 3.555 112.510 4.280 ;
        RECT 113.350 3.555 122.170 4.280 ;
        RECT 123.010 3.555 128.610 4.280 ;
        RECT 129.450 3.555 135.050 4.280 ;
        RECT 135.890 3.555 144.710 4.280 ;
        RECT 145.550 3.555 151.150 4.280 ;
        RECT 151.990 3.555 157.590 4.280 ;
        RECT 158.430 3.555 167.250 4.280 ;
        RECT 168.090 3.555 173.690 4.280 ;
        RECT 174.530 3.555 183.350 4.280 ;
        RECT 184.190 3.555 189.790 4.280 ;
        RECT 190.630 3.555 196.230 4.280 ;
        RECT 197.070 3.555 205.890 4.280 ;
        RECT 206.730 3.555 212.330 4.280 ;
        RECT 213.170 3.555 218.770 4.280 ;
        RECT 219.610 3.555 228.430 4.280 ;
        RECT 229.270 3.555 234.870 4.280 ;
        RECT 235.710 3.555 244.530 4.280 ;
        RECT 245.370 3.555 250.970 4.280 ;
        RECT 251.810 3.555 257.410 4.280 ;
        RECT 258.250 3.555 267.070 4.280 ;
        RECT 267.910 3.555 273.510 4.280 ;
        RECT 274.350 3.555 279.950 4.280 ;
        RECT 280.790 3.555 289.610 4.280 ;
        RECT 290.450 3.555 296.050 4.280 ;
      LAYER met3 ;
        RECT 3.990 286.640 296.000 288.485 ;
        RECT 3.990 285.240 295.600 286.640 ;
        RECT 3.990 283.240 296.000 285.240 ;
        RECT 4.400 281.840 296.000 283.240 ;
        RECT 3.990 276.440 296.000 281.840 ;
        RECT 3.990 275.040 295.600 276.440 ;
        RECT 3.990 273.040 296.000 275.040 ;
        RECT 4.400 271.640 296.000 273.040 ;
        RECT 3.990 269.640 296.000 271.640 ;
        RECT 3.990 268.240 295.600 269.640 ;
        RECT 3.990 266.240 296.000 268.240 ;
        RECT 4.400 264.840 296.000 266.240 ;
        RECT 3.990 262.840 296.000 264.840 ;
        RECT 3.990 261.440 295.600 262.840 ;
        RECT 3.990 259.440 296.000 261.440 ;
        RECT 4.400 258.040 296.000 259.440 ;
        RECT 3.990 252.640 296.000 258.040 ;
        RECT 3.990 251.240 295.600 252.640 ;
        RECT 3.990 249.240 296.000 251.240 ;
        RECT 4.400 247.840 296.000 249.240 ;
        RECT 3.990 245.840 296.000 247.840 ;
        RECT 3.990 244.440 295.600 245.840 ;
        RECT 3.990 242.440 296.000 244.440 ;
        RECT 4.400 241.040 296.000 242.440 ;
        RECT 3.990 235.640 296.000 241.040 ;
        RECT 3.990 234.240 295.600 235.640 ;
        RECT 3.990 232.240 296.000 234.240 ;
        RECT 4.400 230.840 296.000 232.240 ;
        RECT 3.990 228.840 296.000 230.840 ;
        RECT 3.990 227.440 295.600 228.840 ;
        RECT 3.990 225.440 296.000 227.440 ;
        RECT 4.400 224.040 296.000 225.440 ;
        RECT 3.990 222.040 296.000 224.040 ;
        RECT 3.990 220.640 295.600 222.040 ;
        RECT 3.990 218.640 296.000 220.640 ;
        RECT 4.400 217.240 296.000 218.640 ;
        RECT 3.990 211.840 296.000 217.240 ;
        RECT 3.990 210.440 295.600 211.840 ;
        RECT 3.990 208.440 296.000 210.440 ;
        RECT 4.400 207.040 296.000 208.440 ;
        RECT 3.990 205.040 296.000 207.040 ;
        RECT 3.990 203.640 295.600 205.040 ;
        RECT 3.990 201.640 296.000 203.640 ;
        RECT 4.400 200.240 296.000 201.640 ;
        RECT 3.990 198.240 296.000 200.240 ;
        RECT 3.990 196.840 295.600 198.240 ;
        RECT 3.990 194.840 296.000 196.840 ;
        RECT 4.400 193.440 296.000 194.840 ;
        RECT 3.990 188.040 296.000 193.440 ;
        RECT 3.990 186.640 295.600 188.040 ;
        RECT 3.990 184.640 296.000 186.640 ;
        RECT 4.400 183.240 296.000 184.640 ;
        RECT 3.990 181.240 296.000 183.240 ;
        RECT 3.990 179.840 295.600 181.240 ;
        RECT 3.990 177.840 296.000 179.840 ;
        RECT 4.400 176.440 296.000 177.840 ;
        RECT 3.990 171.040 296.000 176.440 ;
        RECT 3.990 169.640 295.600 171.040 ;
        RECT 3.990 167.640 296.000 169.640 ;
        RECT 4.400 166.240 296.000 167.640 ;
        RECT 3.990 164.240 296.000 166.240 ;
        RECT 3.990 162.840 295.600 164.240 ;
        RECT 3.990 160.840 296.000 162.840 ;
        RECT 4.400 159.440 296.000 160.840 ;
        RECT 3.990 157.440 296.000 159.440 ;
        RECT 3.990 156.040 295.600 157.440 ;
        RECT 3.990 154.040 296.000 156.040 ;
        RECT 4.400 152.640 296.000 154.040 ;
        RECT 3.990 147.240 296.000 152.640 ;
        RECT 3.990 145.840 295.600 147.240 ;
        RECT 3.990 143.840 296.000 145.840 ;
        RECT 4.400 142.440 296.000 143.840 ;
        RECT 3.990 140.440 296.000 142.440 ;
        RECT 3.990 139.040 295.600 140.440 ;
        RECT 3.990 137.040 296.000 139.040 ;
        RECT 4.400 135.640 296.000 137.040 ;
        RECT 3.990 133.640 296.000 135.640 ;
        RECT 3.990 132.240 295.600 133.640 ;
        RECT 3.990 130.240 296.000 132.240 ;
        RECT 4.400 128.840 296.000 130.240 ;
        RECT 3.990 123.440 296.000 128.840 ;
        RECT 3.990 122.040 295.600 123.440 ;
        RECT 3.990 120.040 296.000 122.040 ;
        RECT 4.400 118.640 296.000 120.040 ;
        RECT 3.990 116.640 296.000 118.640 ;
        RECT 3.990 115.240 295.600 116.640 ;
        RECT 3.990 113.240 296.000 115.240 ;
        RECT 4.400 111.840 296.000 113.240 ;
        RECT 3.990 106.440 296.000 111.840 ;
        RECT 3.990 105.040 295.600 106.440 ;
        RECT 3.990 103.040 296.000 105.040 ;
        RECT 4.400 101.640 296.000 103.040 ;
        RECT 3.990 99.640 296.000 101.640 ;
        RECT 3.990 98.240 295.600 99.640 ;
        RECT 3.990 96.240 296.000 98.240 ;
        RECT 4.400 94.840 296.000 96.240 ;
        RECT 3.990 92.840 296.000 94.840 ;
        RECT 3.990 91.440 295.600 92.840 ;
        RECT 3.990 89.440 296.000 91.440 ;
        RECT 4.400 88.040 296.000 89.440 ;
        RECT 3.990 82.640 296.000 88.040 ;
        RECT 3.990 81.240 295.600 82.640 ;
        RECT 3.990 79.240 296.000 81.240 ;
        RECT 4.400 77.840 296.000 79.240 ;
        RECT 3.990 75.840 296.000 77.840 ;
        RECT 3.990 74.440 295.600 75.840 ;
        RECT 3.990 72.440 296.000 74.440 ;
        RECT 4.400 71.040 296.000 72.440 ;
        RECT 3.990 69.040 296.000 71.040 ;
        RECT 3.990 67.640 295.600 69.040 ;
        RECT 3.990 65.640 296.000 67.640 ;
        RECT 4.400 64.240 296.000 65.640 ;
        RECT 3.990 58.840 296.000 64.240 ;
        RECT 3.990 57.440 295.600 58.840 ;
        RECT 3.990 55.440 296.000 57.440 ;
        RECT 4.400 54.040 296.000 55.440 ;
        RECT 3.990 52.040 296.000 54.040 ;
        RECT 3.990 50.640 295.600 52.040 ;
        RECT 3.990 48.640 296.000 50.640 ;
        RECT 4.400 47.240 296.000 48.640 ;
        RECT 3.990 41.840 296.000 47.240 ;
        RECT 3.990 40.440 295.600 41.840 ;
        RECT 3.990 38.440 296.000 40.440 ;
        RECT 4.400 37.040 296.000 38.440 ;
        RECT 3.990 35.040 296.000 37.040 ;
        RECT 3.990 33.640 295.600 35.040 ;
        RECT 3.990 31.640 296.000 33.640 ;
        RECT 4.400 30.240 296.000 31.640 ;
        RECT 3.990 28.240 296.000 30.240 ;
        RECT 3.990 26.840 295.600 28.240 ;
        RECT 3.990 24.840 296.000 26.840 ;
        RECT 4.400 23.440 296.000 24.840 ;
        RECT 3.990 18.040 296.000 23.440 ;
        RECT 3.990 16.640 295.600 18.040 ;
        RECT 3.990 14.640 296.000 16.640 ;
        RECT 4.400 13.240 296.000 14.640 ;
        RECT 3.990 11.240 296.000 13.240 ;
        RECT 3.990 9.840 295.600 11.240 ;
        RECT 3.990 7.840 296.000 9.840 ;
        RECT 4.400 6.440 296.000 7.840 ;
        RECT 3.990 4.440 296.000 6.440 ;
        RECT 3.990 3.575 295.600 4.440 ;
      LAYER met4 ;
        RECT 16.855 12.415 20.640 283.385 ;
        RECT 23.040 12.415 23.940 283.385 ;
        RECT 26.340 12.415 174.240 283.385 ;
        RECT 176.640 12.415 177.540 283.385 ;
        RECT 179.940 12.415 193.825 283.385 ;
  END
END timer_axi
END LIBRARY

